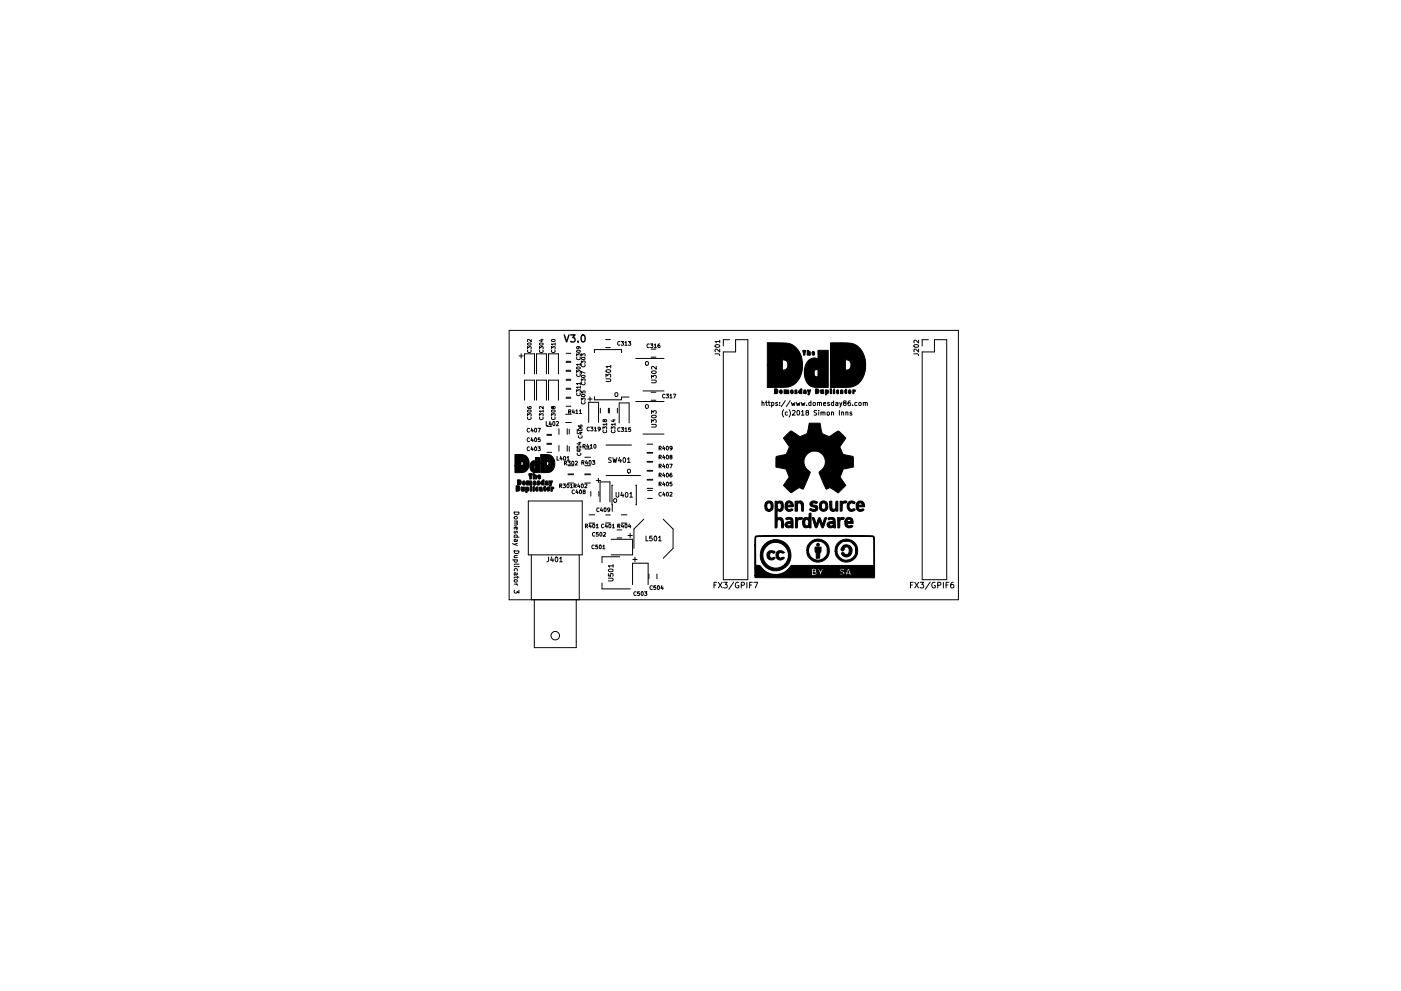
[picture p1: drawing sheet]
<svg xmlns="http://www.w3.org/2000/svg" width="297mm" height="210mm" viewBox="0 0 297 210" stroke-linecap="round" stroke-linejoin="round" font-family="sans-serif">
<path d="M119.6 71.1l.5 1.5 .5-1.5M121 71.1h.9l-.5 .5 .4 .2v.6l-.2 .2-.6-.2M122.6 72.4v.2M123.3 71.2l.3-.1a.8 .8 0 0 1 .5 .7 .8 .8 0 0 1-.5 .8l-.3-.2-.1-.4z" fill="none" stroke="#000" stroke-width=".3"/>
<g fill="none" stroke="#000" stroke-width=".21">
<path d="M107.9 70.1h95.3v57.1h-95.3zM110 75.5h.9M110.5 75.1v.9M111.2 79.3v-4.2h2.1v4.2M111.8 74v-.5l.3 .3 .1-.2h.4v.4M111.9 72.9a.39 .39 0 0 1 .4-.2 .39 .39 0 0 1 .3 .4 .39 .39 0 0 1-.5 .2 .39 .39 0 0 1-.2-.4zM111.9 74.3a.35 .35 0 0 0 .3 .5 .35 .35 0 0 0 .4-.5M112.6 72v.5l-.5-.5-.3 .2 .1 .3M113.8 79.3v-4.2h2.1v4.2M114.4 74v-.5l.3 .3 .1-.2h.3v.4M114.4 72.9a.39 .39 0 0 1 .5-.2 .39 .39 0 0 1 .2 .4 .39 .39 0 0 1-.4 .2 .39 .39 0 0 1-.3-.4zM114.4 74.3a.35 .35 0 0 0 .4 .5 .35 .35 0 0 0 .3-.5"/>
<path d="M114.6 72.1h.6M114.9 72v.5l-.6-.2M116.3 79.3v-4.2h2.1v4.2M116.9 74v-.5l.3 .3 .1-.2h.3v.4M116.9 72.1a.39 .39 0 0 1 .5-.1 .39 .39 0 0 1 .3 .4 .39 .39 0 0 1-.5 .1 .39 .39 0 0 1-.3-.4zM117 74.3a.35 .35 0 0 0 .3 .5 .35 .35 0 0 0 .3-.5M117.7 73h-.8l.2 .2M117.7 72.8v.4M120 78.8h1M120 78.6h1M120 76.9h1M120 76.7h1"/>
<path d="M120 75h1M122.2 79.1v-.5l.3 .3 .1-.2h.4v.4M122.2 75.6v-.5l.3 .2 .1-.2h.4v.5M122.3 78a.39 .39 0 0 1 .4-.2 .39 .39 0 0 1 .3 .4 .39 .39 0 0 1-.4 .2 .39 .39 0 0 1-.3-.4zM122.3 79.4a.35 .35 0 0 0 .3 .5 .35 .35 0 0 0 .4-.5M122.3 75.8a.35 .35 0 0 0 .3 .5 .35 .35 0 0 0 .4-.5M122.3 74.4a.38 .38 0 0 1 .5-.1 .38 .38 0 0 1 .2 .3 .39 .39 0 0 1-.4 .2 .39 .39 0 0 1-.3-.4zM122.6 73.5l.1 .4-.4 .1-.1-.3 .2-.2 .5 .1 .1 .3M123 77.3h-.8l.3 .2M123 77.1v.4M123.3 77.1v-.5l.3 .2v-.2h.4v.5M123.3 75.6v-.5l.3 .2v-.2h.4v.5"/>
<path d="M123.3 75.9a.39 .39 0 0 1 .5-.1 .39 .39 0 0 1 .2 .4 .39 .39 0 0 1-.4 .1 .39 .39 0 0 1-.3-.4zM123.3 79.7a.39 .39 0 0 1 .5-.1 .39 .39 0 0 1 .2 .4 .39 .39 0 0 1-.4 .1 .39 .39 0 0 1-.3-.4zM123.3 77.3a.35 .35 0 0 0 .4 .5 .35 .35 0 0 0 .3-.5M124.1 79.2l-.8-.4v.6M126 74.8v-.6h5.8v.6M128.4 72h1M128.4 73.7h1M128.5 78.6a.49 .49 0 0 1 .6-.2 .49 .49 0 0 1 .3 .5 .49 .49 0 0 1-.5 .2 .49 .49 0 0 1-.4-.5zM129.5 77.8h-1l.3 .3M129.5 77.5v.6M131.4 72.5a.35 .35 0 0 0-.5 .4 .35 .35 0 0 0 .5 .3M131.7 72.5h.5l-.3 .3h.3v.4h-.5"/>
<path d="M132.5 72.7l.2-.2v.8M132.5 73.3h.5M133.2 72.5h.5l-.2 .3h.2v.4h-.5M134.8 76h6M136.9 76.8l.2-.1 .3 .1v.6h-.5zM137.7 73a.35 .35 0 0 0-.5 .4 .35 .35 0 0 0 .5 .3M137.9 73h.5l-.2 .3h.2v.4h-.5M138.1 75.8h1M138.1 74.1h1M138.2 78.8a.49 .49 0 0 1 .5-.2 .49 .49 0 0 1 .4 .5 .49 .49 0 0 1-.6 .2 .49 .49 0 0 1-.3-.5zM138.7 73.2l.3-.2v.8M138.7 73.8h.5"/>
<path d="M139.1 77.7v.7l-.7-.7-.3 .2 .1 .4M139.9 73l-.4 .2v.4l.1 .2 .3-.1v-.4l-.4 .1M151.6 75.1h.9l.1 .3M151.7 73.2a.48 .48 0 0 1 .5-.1 .48 .48 0 0 1 .4 .4 .49 .49 0 0 1-.6 .3 .49 .49 0 0 1-.4-.5zM152.6 74.1v.6l-.7-.6-.3 .2 .1 .3M152.6 72.4h-1l.3 .3M152.6 72.2v.5M153.4 74.7h2.6v-2.6h2.6v50.9h-5.2zM154.7 72.1h-1.3v1.3M193.8 75.1h.8l.2 .3M193.9 73.2a.48 .48 0 0 1 .5-.1 .48 .48 0 0 1 .3 .4 .49 .49 0 0 1-.6 .3 .49 .49 0 0 1-.3-.5zM194.8 74.1v.6l-.8-.6-.2 .2 .1 .3"/>
<path d="M194.8 72.2v.6l-.8-.6-.2 .2 .1 .3M195.5 74.7h2.6v-2.6h2.6v50.9h-5.2zM196.8 72.1h-1.3v1.3M111.2 84.9v-4.2h2.1v4.2M111.8 88.3v-.5l.3 .2 .1-.2h.4v.5M111.8 86.3l.2 .4h.5l.1-.2v-.2h-.4l.1 .4M111.9 88.5a.35 .35 0 0 0 .3 .5 .35 .35 0 0 0 .4-.5M111.9 87.1a.38 .38 0 0 1 .4-.1 .38 .38 0 0 1 .3 .3 .39 .39 0 0 1-.5 .2 .39 .39 0 0 1-.2-.4zM112.3 94.9a.35 .35 0 0 0-.5 .3 .35 .35 0 0 0 .5 .3M112.3 93a.35 .35 0 0 0-.5 .3 .35 .35 0 0 0 .5 .3M112.3 90.9a.35 .35 0 0 0-.5 .4 .35 .35 0 0 0 .5 .3M112.8 94.8l-.2 .5h.5"/>
<path d="M112.8 92.9l-.2 .5h.5M112.8 90.8l-.2 .6h.5M112.9 91.1v.6M112.9 93.2v.5M112.9 95.1v.5M113.4 94.9l.1-.1a.37 .37 0 0 1 .3 .4 .37 .37 0 0 1-.4 .3zM113.4 93l.1-.1a.37 .37 0 0 1 .3 .4 .37 .37 0 0 1-.4 .3zM113.4 90.9h.1a.37 .37 0 0 1 .3 .4 .37 .37 0 0 1-.4 .3zM113.8 84.9v-4.2h2.1v4.2M114.1 94.8h.4l-.2 .3 .2 .1v.3h-.4M114.1 90.9h.5l-.4 .8M114.4 88.3v-.5l.3 .2 .1-.2h.3v.5"/>
<path d="M114.4 88.5a.35 .35 0 0 0 .4 .5 .35 .35 0 0 0 .3-.5M114.5 92.9h-.4v.4l.4-.1v.4h-.4M115.2 87.2h-.8l.2 .3M115.2 86.2v.5l-.6-.5-.2 .2v.3M115.2 87v.5M115.8 89.4v.9h.4M116 96h1M116 94.3h1M116 94.1h1M116 92.4h1M116 92.2h1M116 90.5h1"/>
<path d="M116.3 84.9v-4.2h2.1v4.2M116.6 89.4l-.2 .6h.5M116.8 89.7v.6M116.9 88.3v-.5l.3 .2 .1-.2h.3v.5M116.9 87.1a.39 .39 0 0 1 .5-.2 .39 .39 0 0 1 .3 .4 .39 .39 0 0 1-.5 .2 .39 .39 0 0 1-.3-.4zM117 88.5a.35 .35 0 0 0 .3 .5 .35 .35 0 0 0 .3-.5M117.3 86.4l.3-.1v.4a.33 .33 0 0 1-.3-.1 .33 .33 0 0 1-.1-.3h-.3v.2l.2 .2 .2-.2M117.3 89.5l.1-.1a.45 .45 0 0 1 .3 .5 .45 .45 0 0 1-.4 .4l-.1-.3zM118 89.5l.3-.1 .1 .3-.5 .6h.5M118.1 96.8v.8h.4M118.5 91v1.2M118.5 94.5v1.2"/>
<path d="M118.9 96.8l-.2 .6h.5M119.1 97.1v.5M119.6 96.9l.1-.1a.37 .37 0 0 1 .3 .5 .37 .37 0 0 1-.4 .3zM119.7 98.3l.4-.1v-.3h-.4v.8M119.9 98.3l.2 .4M119.9 89.6h1.2M119.9 87.9h1.2M120 80.5h1M120 86.2h1M120 84.5h1M120 80.7h1M120 82.4h1"/>
<path d="M120 84.3h1M120 82.6h1M120.2 97.1l.3-.3v.8M120.2 97.6h.5M120.3 91v1.2M120.3 94.5v1.2M120.4 97.9h.5l-.3 .3h.3v.4h-.5M120.4 98.8h1.2M120.6 87.4l.3-.1 .1-.3-.4-.1v.8M120.7 91.1v1M120.7 94.7v1M120.8 87.4l.2 .3"/>
<path d="M121.3 97.9h.1a.37 .37 0 0 1 .3 .4 .37 .37 0 0 1-.4 .3zM121.5 86.9l-.2 .6h.5M121.7 87.2v.5M122 97.9h.3l.1 .2-.5 .6h.5M122.1 87.2l.2-.3v.8M122.1 87.7h.4M122.2 83.2v-.5l.3 .2 .1-.2h.4v.5M122.3 83.4a.35 .35 0 0 0 .3 .5 .35 .35 0 0 0 .4-.5M122.4 91.1v1M122.4 94.7v1M122.4 94.7a.39 .39 0 0 1 .5-.1 .39 .39 0 0 1 .2 .4 .39 .39 0 0 1-.4 .1 .39 .39 0 0 1-.3-.4zM122.4 96.1a.35 .35 0 0 0 .4 .5 .35 .35 0 0 0 .3-.5"/>
<path d="M122.6 90.2l.2 .4h.5l.1-.1-.1-.3h-.3l.1 .4M122.6 95.5h.6M122.6 93.9h.6M122.7 91a.39 .39 0 0 1 .4-.1 .39 .39 0 0 1 .3 .4 .39 .39 0 0 1-.5 .1 .39 .39 0 0 1-.2-.4zM122.7 92.5a.35 .35 0 0 0 .3 .5 .35 .35 0 0 0 .3-.5M122.9 87.2l.2-.3v.8M122.9 87.7h.4M122.9 91.8h.5M122.9 95.3v.5l-.6-.2M122.9 93.8v.5l-.6-.2M123 82.1h-.8l.3 .3M123 81.4h-.8l.3 .2"/>
<path d="M123 81.2v.4M123 81.9v.5M123.2 91.7v.5l-.6-.2M123.3 85v-.5l.3 .2v-.2h.4v.5M123.3 83v.4h.3v-.4h.4v.4M123.3 80.9v-.5l.3 .3v-.3h.4v.5M123.3 83.8a.39 .39 0 0 1 .5-.2 .39 .39 0 0 1 .2 .4 .39 .39 0 0 1-.4 .2 .39 .39 0 0 1-.3-.4zM123.3 85.2a.35 .35 0 0 0 .4 .5 .35 .35 0 0 0 .3-.5M123.3 81.2a.35 .35 0 0 0 .4 .5 .35 .35 0 0 0 .3-.5M123.4 98.1h.3l.1-.3-.4-.1v.8M123.6 98.1l.2 .4M123.6 94.7h.4v-.3l-.4-.1v.8"/>
<path d="M123.8 94.7l.3 .4M124 98.8h1.2M124 95.3h1.2M124 97h1.2M124.3 97.7l-.2 .6h.5M124.5 98v.5M124.6 94.3l-.2 .5h.5M124.6 84.7h1M124.8 94.6v.5M124.8 89.6v-4.2h2.1v4.2M125 90.7a.35 .35 0 0 0-.5 .3 .35 .35 0 0 0 .5 .3M125 97.8l.1-.1a.37 .37 0 0 1 .3 .4 .37 .37 0 0 1-.4 .4z"/>
<path d="M125.1 84.2v.9M125.1 94.5l.3-.2v.8M125.1 95.1h.5M125.2 90.6h.5l-.2 .3 .2 .1v.3h-.5M125.6 97.7h.5l-.3 .3 .3 .1v.4h-.5M126 94.3h.1a.37 .37 0 0 1 .3 .4 .37 .37 0 0 1-.4 .3zM126 90.8l.3-.2v.8M126 91.4h.5M126 84.2v.6h5.8v-.6h1.6M127.2 91l-.3 .1-.1-.4 .3-.1 .1 .2v.4l-.3 .2M127.3 86.6v1M127.8 91v-.4l.3 .2 .1-.2h.4v.4"/>
<path d="M127.9 91.3a.35 .35 0 0 0 .3 .5 .35 .35 0 0 0 .4-.5M128.2 89.2l.4-.1v.3a.33 .33 0 0 1-.4 0 .33 .33 0 0 1-.1-.3h-.2l-.1 .2 .2 .2 .2-.2M128.5 80.4h.8l.2 .2-.2 .4h-.8M128.5 80v-.6l.4 .3 .1-.3h.4v.6M128.5 94.4h5.4M128.6 90h-.8l.3 .2M128.6 89.8v.4M129 86.6v1M129.2 86.6v1M129.6 97.2h-.5a.42 .42 0 0 0 .5 .5l-.1 .4h-.5M129.6 91v-.4l.3 .2 .1-.2h.3v.4M129.7 91.3a.35 .35 0 0 0 .3 .5 .35 .35 0 0 0 .3-.5"/>
<path d="M129.9 89.1h.5M129.9 97.1l.3 1 .2-.7 .2 .7 .2-1M130.1 89v.5l-.5-.2M130.4 90h-.8l.2 .2M130.4 89.8v.4M130.4 83.4l.2-.1 .3 .1v.6h-.5zM130.9 86.6v1M131.3 89.7v-4.2h2.1v4.2M131.4 97.1l-.3 .7h.6M131.4 90.8a.35 .35 0 0 0-.5 .3 .35 .35 0 0 0 .5 .4M131.6 97.4v.7M131.7 90.7h.5l-.3 .3 .3 .1v.4h-.5"/>
<path d="M132.2 97.2l.1-.1a.49 .49 0 0 1 .4 .5 .49 .49 0 0 1-.5 .5l-.1-.4zM132.5 91l.2-.3v.8M132.5 91.5h.5M133 97.4l.3-.3v1M133 98.1h.6M133.1 99.7l.2-.1 .3 .1-.1 .6-.4-.1zM133.7 90.7h-.4v.4h.3l.1 .4h-.4M134.8 85.2h6M136.3 82.9h4.5M136.3 92.1h4.5M136.9 86l.2-.2 .3 .2v.6l-.5-.1zM137.2 100h1.2"/>
<path d="M137.2 96h1.2M137.2 94.2h1.2M137.2 98h1.2M137.2 99.8h1.2M137.2 96.1h1.2M137.2 97.9h1.2M138.1 84.9h1M138.1 83.2h1M138.1 80.6h.8l.2 .2-.2 .4h-.8M138.1 80.3v-.7l.4 .4 .1-.3h.4v.6M138.1 90h.8l.2 .2-.2 .4h-.8M138.1 89.7v-.7l.4 .4 .1-.3h.4v.6"/>
<path d="M138.1 87.8v-.7l.4 .4 .1-.3h.4v.6M138.2 88.2a.49 .49 0 0 1 .5-.2 .49 .49 0 0 1 .4 .5 .49 .49 0 0 1-.6 .2 .49 .49 0 0 1-.3-.5zM139.7 98.9h.4l.1-.3-.5-.1v.8M139.7 97h.4l.1-.3-.5-.1v.8M139.7 95.1h.4l.1-.3-.5-.1v.8M139.9 98.9l.3 .4M139.9 97l.3 .4M139.9 95.1l.3 .4M140.7 98.5l-.2 .5h.5M140.7 96.5l-.2 .6h.5M140.7 94.6l-.2 .6h.5M140.9 94.9v.6"/>
<path d="M140.9 96.9v.5M140.9 98.8v.5M141 83.7a.35 .35 0 0 0-.5 .3 .35 .35 0 0 0 .5 .4M141.2 83.6h.5l-.2 .3 .2 .1v.4h-.5M141.3 98.6l.2-.1a.37 .37 0 0 1 .2 .4 .37 .37 0 0 1-.4 .3zM141.3 96.7l.2-.1a.37 .37 0 0 1 .2 .4 .37 .37 0 0 1-.4 .3zM141.3 94.8l.2-.1a.37 .37 0 0 1 .2 .4 .37 .37 0 0 1-.4 .3zM142 98.5h.5l-.3 .8M142 83.9l.3-.3v.8M142 84.4h.5M142.2 96.9l-.2-.1 .2-.2 .2 .1v.2a.32 .32 0 0 0-.3 .1 .32 .32 0 0 0 0 .3h.3l-.1-.4M142.5 95l-.4 .1v-.3l.2-.1 .2 .1-.1 .5-.3 .2"/>
<path d="M142.8 83.6h.5l-.4 .8M161.6 85.5l.3-.1 .1 .6M161.6 85v1M162.3 85.4h.4M162.5 85v.9l.2 .1M162.9 85.4h.4M163 85v.9l.3 .1M163.6 85.4h.3l.2 .2-.1 .4h-.4M163.6 85.4v1M164.8 85.4l-.3 .1 .3 .3v.2h-.3M165.3 85.9v.1M165.3 85.4v.1"/>
<path d="M166.2 86.9a1.15 1.15 0 0 0 0 1.6M166.5 85l-.9 1.3M167 87.5l-.3-.1-.2 .2 .1 .4h.4M167.3 86.9a1.15 1.15 0 0 1 0 1.6M167.6 85l-.9 1.3M167.8 85.4l.2 .6 .2-.4 .2 .4 .2-.6M168 87.2l.4-.1 .2 .3-.6 .7h.6M168.8 85.4l.2 .6 .2-.4 .2 .4 .2-.6M169.1 87.1h.1a.49 .49 0 0 1 .4 .5 .49 .49 0 0 1-.5 .4l-.1-.3zM169.9 85.4l.2 .6 .2-.4 .2 .4 .1-.6M169.9 87.4l.3-.3v1M169.9 88.1h.6"/>
<path d="M171 85.9v.1M171.1 87.5l-.2-.3 .4-.1 .1 .3-.5 .3 .2 .4 .3-.2-.1-.4M171.9 85.4h-.3l-.1 .2 .1 .4h.3M171.9 85v1M172.4 85.5h.4v.5l-.4-.1zM173.2 87.1l-.6 .1a.42 .42 0 0 0 .5 .5v.3h-.5M173.3 85.5l.4-.1v.6M173.3 85.4v.6M173.6 87.1v.1M173.6 87.4v.7M173.7 85.5l.4-.1 .1 .6M174.1 87.5h.3l.1 .6"/>
<path d="M174.1 87.4v.7M174.5 87.6l.4-.1v.6M174.6 85.7l.5-.1-.1-.2h-.3l-.1 .1v.5h.4M175.4 87.5h.4v.5h-.4zM175.8 85.4l-.3 .1 .3 .3v.2h-.3M176.3 87.5h.4v.6M176.3 87.4v.7M176.7 85.4h-.2l-.2 .2 .1 .4h.3M176.7 85v1M177.2 85.4h.4v.6M177.6 85.6l-.4 .2 .1 .2h.3M178 87.1v1"/>
<path d="M178 85.4l.3 .6M178.4 87.5h.4l.1 .6M178.4 87.4v.7M178.5 85.4l-.5 1M179 85.5l-.1-.4h.4l.1 .3-.6 .3 .2 .3 .4-.1-.2-.4M179.3 87.5h.4l.1 .6M179.3 87.4v.7M180.3 85l-.5 .3v.6l.2 .1 .3-.1v-.4l-.3-.1-.2 .2M180.6 87.5l-.4 .1 .4 .2v.2h-.4M180.8 85.9v.1M181.7 85.4h-.3l-.2 .2 .1 .4h.4M182.2 85.4h.2l.2 .2v.3l-.2 .1-.3-.1z"/>
<path d="M183 85.5l.4-.1 .1 .6M183 85.4v.6M183.5 85.5l.3-.1 .1 .6M108.7 115.3l1 .4M108.7 118.8h.9v.4h-.5v-.4M109 108.6h1a.51 .51 0 0 1-.5 .6 .51 .51 0 0 1-.5-.6zM109 116.9h1a.51 .51 0 0 1-.5 .6 .51 .51 0 0 1-.5-.6zM109 110.5h.7M109 114h1M109 118.3h.7M109.1 109.7l.4-.1 .2 .3-.2 .2h-.3l-.2-.2zM109.1 112.7v.4h.2l.2-.4 .2 .1-.1 .3"/>
<path d="M109.1 114l-.1-.3 .2-.2 .4 .1v.4M109.1 114.9l-.1-.4 .2-.1 .2 .1 .1 .4M109.4 111.8l.1 .5h.1l.1-.3-.2-.2-.4 .1v.4M109.5 111l.1 .4h-.6M109.6 110.5v.4l-.6 .1M109.6 114.5v.3l-.6 .1M109.7 117.9h-.6v.4M109.7 115.3l-.7 .2M110 119.7h-.8l-.2 .1M112 106.3h11.4v11.4h-11.4zM112.6 117.7v9.5M116.3 118.2v.8l-.4 .2"/>
<path d="M117 118.1l-.3 .8h.7M117.2 118.5v.7M117.8 118.2h.1a.49 .49 0 0 1 .4 .5 .49 .49 0 0 1-.5 .4l-.1-.3zM118.6 118.5l.3-.3v1M118.6 119.2h.6M118.7 103.1h.3l.1-.3-.4-.1v.8M118.9 103.1l.2 .4M119.4 102.7h.5l-.3 .3 .2 .1v.3h-.4M120.3 102.8l.1-.1a.37 .37 0 0 1 .3 .4 .37 .37 0 0 1-.4 .3zM120.4 100.7h1.2M120.4 102.5h1.2M120.4 100.6h1.2"/>
<path d="M120.9 102.9l.3-.2v.8M120.9 103.5h.5M121.7 103.1h.4v-.3l-.4-.1v.8M121.8 104a.35 .35 0 0 0-.5 .4 .35 .35 0 0 0 .5 .3M121.9 103.1l.3 .4M122.3 103.9l-.2 .6h.5M122.5 104.2v.6M122.7 102.6l-.2 .6h.5M122.8 117.7v9.5M122.9 102.9v.6M122.9 104h.1a.37 .37 0 0 1 .3 .4 .37 .37 0 0 1-.4 .3zM123.3 102.8l.1-.1a.37 .37 0 0 1 .3 .4 .37 .37 0 0 1-.4 .3z"/>
<path d="M123.8 104.3l-.2-.2 .2-.1h.2v.2a.32 .32 0 0 0-.3 .1 .32 .32 0 0 0 0 .4h.3l-.1-.4M124 100.7h1.2M124 102.5h1.2M124 100.6h1.2M124 102.8l.3-.1 .2 .2-.5 .6h.5M124.1 111.6h.4v-.3l-.4-.1v.8M124.3 111.6l.3 .4M124.9 109.2h1.2M124.9 111h1.2M125.1 111.2l-.2 .5h.5M125.3 104.3v1M125.3 111.5v.5"/>
<path d="M125.7 111.3l.1-.1a.37 .37 0 0 1 .3 .4 .37 .37 0 0 1-.4 .3zM126 115.7a.35 .35 0 0 0-.5 .3 .35 .35 0 0 0 .5 .4M126.1 113a.35 .35 0 0 0-.5 .4 .35 .35 0 0 0 .5 .3M126.4 111.4l.2-.2v.8M126.4 112h.5M126.4 101.9h.9M126.7 115.6h-.4v.4h.4v.4h-.4M126.8 113h-.4v.3h.4v.4h-.4M126.9 101.5v.9M127 104.3v1M127 107.8a.35 .35 0 0 0-.5 .4 .35 .35 0 0 0 .5 .3M127.1 115.7l.1-.1a.37 .37 0 0 1 .3 .5 .37 .37 0 0 1-.4 .3z"/>
<path d="M127.2 106.5v-4.3h2.1v4.3M127.2 113h.2a.37 .37 0 0 1 .3 .4 .37 .37 0 0 1-.5 .3zM127.5 107.7l-.2 .6h.5M127.7 108v.6M127.8 115.9l.2-.3v.8M127.8 116.4h.5M127.9 113h.3l.2 .2-.5 .6h.5M128 111.3a.35 .35 0 0 0-.5 .3 .35 .35 0 0 0 .5 .3M128.1 107.8h.2a.37 .37 0 0 1 .2 .4 .37 .37 0 0 1-.4 .3zM128.4 111h1M128.4 109.3h1M128.5 100.9h7.3"/>
<path d="M128.5 111.2l-.2 .5h.5M128.7 111.5v.5M129.2 111.2h.1a.37 .37 0 0 1 .3 .4 .37 .37 0 0 1-.4 .3zM129.3 108.1l-.4 .1v-.4h.2l.2 .1-.1 .5-.3 .2M129.6 114.4h4.5v3.3h-4.5M129.8 111.4l.3-.2v.8M129.8 112h.5M129.9 102.9h-.1v5.6M130 119.8v.5M130.2 105.9l.1-.1 .4 .1-.1 .6h-.4zM130.6 104.5v.8l.2 .2 .4-.2v-.8M130.8 114.1h1"/>
<path d="M130.8 112.4h1M131 111.6h.4v-.3l-.4-.1v.8M131.2 111.6l.2 .4M131.4 118.1h-3.8v1.3M131.7 109.2h1.2M131.7 111h1.2M131.9 104.4l-.3 .7h.6M131.9 111.2l-.2 .5h.5M132.1 104.8v.7M132.1 111.5v.5M132.6 111.2h.1a.37 .37 0 0 1 .3 .4 .37 .37 0 0 1-.4 .3zM132.7 104.6l.1-.1a.49 .49 0 0 1 .4 .5 .49 .49 0 0 1-.5 .4l-.1-.3z"/>
<path d="M133.1 113.6h1M133.5 111.2l-.2 .5h.5M133.5 104.8l.3-.3v1M133.5 105.5h.6M133.6 113.2v.9M133.6 111.5v.5M134.2 118.7h.9M134.6 118.2v1M134.8 102.9h.1v4.2h-.1M136.5 110.1l-2.1 2.1v4.1M137 113.7v1h.4M137.2 103.6h1.2"/>
<path d="M137.2 101.9h1.2M137.2 101.7h1.2M137.3 104h1M137.3 105.7h1M138.2 113.7h-.4l-.1 .5h.5v.5h-.5M138.8 113.8l.1-.1a.49 .49 0 0 1 .4 .6 .49 .49 0 0 1-.5 .4l-.1-.3zM139.6 114l.3-.3v1M139.6 114.7h.6M139.7 102.7h.4l.1-.3-.5-.1v.8M139.7 100.8h.4l.1-.3-.5-.1v.8M139.9 102.7l.3 .4M139.9 100.8l.3 .4"/>
<path d="M140.2 104.5a.35 .35 0 0 0-.5 .4 .35 .35 0 0 0 .5 .3M140.6 110.1l2.1 2.1v4.1l-2.1 2.1M140.7 104.4l-.2 .6h.5M140.7 102.3l-.2 .5h.5M140.7 100.4l-.2 .5h.5M140.9 100.7v.5M140.9 102.6v.5M140.9 104.7v.6M141.3 104.5h.2a.37 .37 0 0 1 .2 .4 .37 .37 0 0 1-.4 .3zM141.3 102.4l.2-.1a.37 .37 0 0 1 .2 .4 .37 .37 0 0 1-.4 .3zM141.3 100.5l.2-.1a.37 .37 0 0 1 .2 .4 .37 .37 0 0 1-.4 .3zM142 104.5h.3l.2 .2-.5 .6h.5"/>
<path d="M142.4 100.4l-.3 .2-.1 .4 .2 .2 .2-.1v-.4l-.4 .2M142.4 102.3h-.3l-.1 .4 .4-.1v.4h-.4M109 120.2h.7M109 123.9h.7M109.1 121.1l-.1-.3 .2-.2 .4 .1v.4M109.1 122l-.1-.4 .2-.1h.2l.1 .5M109.1 123h.5v.4l-.5 .1zM109.1 125.2l-.1 .4 .2 .2h.3l.1-.3 .4 .3v-.6M109.5 123.9l.2 .3M109.6 121.5v.4l-.6 .1M109.7 122.3v.4M109.9 120.2h.1"/>
<path d="M110 122.5h-.8l-.2 .2M113.3 127.2v10.2h8.9v-10.2M127.6 123.7v1.2h6M129 122.7h.8l.2 .2-.2 .3h-.8M129 121.7v.5h.5l-.1-.4 .5-.1v.5M129 120.9a.49 .49 0 0 1 .6-.2 .49 .49 0 0 1 .3 .5 .49 .49 0 0 1-.5 .2 .49 .49 0 0 1-.4-.5zM130 120.1h-1l.3 .2M134.1 124v-4.5h3.3v4.5M134.9 125.6a.35 .35 0 0 0-.5 .3 .35 .35 0 0 0 .5 .4M135.6 125.5h-.4v.4h.4v.4h-.4M136 125.6l.1-.1a.37 .37 0 0 1 .3 .5 .37 .37 0 0 1-.4 .3zM136.7 125.5h.5l-.3 .3 .2 .1v.4h-.4"/>
<path d="M137.6 121.8v1M138.3 124.3a.35 .35 0 0 0-.5 .4 .35 .35 0 0 0 .5 .3M139 124.3h-.4v.4l.4-.1v.4h-.4M139.3 121.8v1M139.5 124.3h.1a.37 .37 0 0 1 .2 .4 .37 .37 0 0 1-.4 .3zM140.3 124.2l-.2 .6h.5M140.5 124.5v.6M151.4 124.1h.4M152 123.5h-.6v1.2M152.3 123.5l.8 1.2M153.1 123.5l-.8 1.2M153.4 123.5h.8l-.4 .5 .3 .1v.5l-.1 .1-.6-.1"/>
<path d="M155.6 123.5l-1.1 1.5M156.6 123.6a.55 .55 0 0 0-.7 .6 .55 .55 0 0 0 .7 .4v-.4h-.2M157.2 124.2l.5-.1 .1-.4-.6-.2v1.2M158.4 123.5v1.2M158.9 124.1h.4M159.5 123.5h-.6v1.2M159.8 123.5h.8l-.5 1.2M193 124.1h.4M193.6 123.5h-.6v1.2M194 123.5l.8 1.2M194.8 123.5l-.8 1.2M195.1 123.5h.7l-.4 .5 .4 .1v.5l-.2 .1-.5-.1"/>
<path d="M197.2 123.5l-1 1.5M198.2 123.6a.55 .55 0 0 0-.7 .6 .55 .55 0 0 0 .8 .4v-.4h-.2M198.8 124.2l.6-.1v-.4l-.6-.2v1.2M200 123.5v1.2M200.6 124.1h.4M201.2 123.5h-.6v1.2M202.1 123.5l-.3 .1-.2 .2v.7l.2 .2 .4-.1-.1-.5-.3-.1-.2 .2"/>
<circle cx="117.7" cy="134.9" r=".9"/>
</g>
<g fill="#000" stroke="#000" stroke-width=".21">
<path d="M162.7 72.7h2.5a4 4 0 0 1 4.7 3 5.2 5.2 0 0 1-2.2 6.2l-1.1 .3h-3.9v-4.7h3.2v1a1.06 1.06 0 0 0 1.2-1 1.06 1.06 0 0 0-1.2-1.1v1.1h-3.2zM170.2 74.3h.6l-.1 1h-.4zM171.2 74.3l.2 .1 .1 .2h.2l.1 .7h-.3v-.5v.5h-.3zM172.3 74.6a.25 .25 0 0 1 .3 .1 .25 .25 0 0 1 0 .3h-.2l.3 .1v.2h-.4l-.1-.5h.4h-.4zM173.4 74.3h2.2v7.9h-1.7a2.72 2.72 0 0 1-3.4-3h2.1l.1 .5 .6 .2h.1v-.6a.55 .55 0 0 0-.3-.9l-.3 .1-.2 .7h-2.1a2.83 2.83 0 0 1 2-3.2l.9 .1zM176.1 72.7h2.7a4.1 4.1 0 0 1 4.7 4.3 4.3 4.3 0 0 1-3.3 5.1l-4.1 .1v-3.7h3.1a1.11 1.11 0 0 0 1.2-1.1 1.11 1.11 0 0 0-1.2-1.1v2.2h-3.1zM109.2 96.4a2.99 2.99 0 0 1 2.5 .5 2.01 2.01 0 0 1-.9 3.3l-1.6 .1v-1.5h1.2a.42 .42 0 0 0 .6-.4 .42 .42 0 0 0-.5-.4l-.1 .8h-1.2zM113.5 97.1h.9v3.2h-1.1a1.07 1.07 0 0 1-.9-1.3h.8l.1 .3h.2l-.1-.6-.2 .3h-.8a.95 .95 0 0 1 1.1-1.2zM114.6 96.4h.9a1.93 1.93 0 0 1 2.1 1.6 1.93 1.93 0 0 1-1.5 2.2l-1.5 .1v-2.1h1.3v.5a.38 .38 0 0 0 .5-.4 .38 .38 0 0 0-.5-.3v.2h-1.3zM164.2 82.5a.54 .54 0 0 1 .7 .5 .54 .54 0 0 1-.7 .5v-.5l.4 .1v-.1v-.1l-.4 .1zM165.4 82.8a.36 .36 0 0 1 .5 .3 .36 .36 0 0 1-.5 .4l-.1-.4h.3h-.3zM166.2 82.7h.9l.2 .8h-.3l-.1-.5v.5h-.3v-.5l-.1 .5h-.3z"/>
<path d="M167.7 82.8l.4 .1 .1 .3h-.3l.3 .2a.33 .33 0 0 1-.5 .1 .33 .33 0 0 1-.1-.5h.4h-.4zM168.6 82.7l.4 .1-.2 .2a.27 .27 0 0 1 .2 .3 .27 .27 0 0 1-.2 .2h-.3l.1-.2h.2l-.3-.3zM169.5 82.8l.5-.3v1l-.6-.1v-.2h.4l-.1-.2-.1 .2h-.2zM170.4 82.8a.34 .34 0 0 1 .5 0 .34 .34 0 0 1 0 .4v.3h-.5v-.2h.2h-.2l.2-.2-.2-.1zM171.2 82.7h.2l.1 .2 .1-.1 .3-.1-.1 .2a.78 .78 0 0 1-.4 .9l-.1-.1 .1-.3zM172.9 82.5a.54 .54 0 0 1 .7 .5 .54 .54 0 0 1-.7 .5v-.5l.4 .1v-.1v-.1l-.4 .1zM166.8 92.2l.9-.8 1.9 1.2 1.3-.5 .3-.2 .4-2.1h2.3l.2 1.4a1.02 1.02 0 0 0 1.1 1.2l.7 .3 1.8-1.3 .9 .8 .7 .8-1.2 1.8 .3 .8a1.02 1.02 0 0 0 1.3 1l1.2 .3v2.2l-2.1 .4-.7 1.7 1.2 1.8-1.6 1.6-1.1-.8a.97 .97 0 0 0-1.4 0l-1.5-3.6a2.41 2.41 0 0 0 1.3-2.3 2.41 2.41 0 0 0-1.7-2.1 2.35 2.35 0 0 0-2.7 1.5 2.35 2.35 0 0 0 1.2 2.9l-1.5 3.6a1.04 1.04 0 0 0-1.4 0l-1.2 .8-1.6-1.6 1.2-1.8-.7-1.7-2.1-.4 .1-2.2 1.2-.3a1.02 1.02 0 0 0 1.2-1l.4-.8-1.3-1.8zM174 82.7h.2l.1 .6 .1-.6h.2v.8h-.5zM175 82.7a.45 .45 0 0 1 .6 .2 .45 .45 0 0 1-.2 .6l-.4 .3v-.7h.3v.2l.1-.2h-.4zM176 82.5h.3v1h-.3zM176.7 82.8h.3v.7h-.3zM177.4 82.8h.4v.3h-.2l.2 .1a.27 .27 0 0 1-.3 .3 .27 .27 0 0 1-.2-.4z"/>
<path d="M178.2 82.8a.33 .33 0 0 1 .4 0 .33 .33 0 0 1 .1 .4v.3h-.5v-.2h.3h-.3l.2-.3h-.2zM179.3 82.6l.2 .2v.7a.5 .5 0 0 1-.4-.4 .5 .5 0 0 1 .2-.5zM180 82.8a.35 .35 0 0 1 .4 .3 .35 .35 0 0 1-.4 .4l-.1-.4h.3h-.3zM180.8 82.7h.5v.3a.33 .33 0 0 0-.3 .5h-.2zM109.4 103.1a.59 .59 0 0 1 .8 .4 .59 .59 0 0 1-.4 .7h-.4v-.6h.4v.2l.1-.2-.1-.1v.1h-.4zM109.7 101.8a.59 .59 0 0 1 .8 .6 .59 .59 0 0 1-.8 .5v-.5l.4 .1 .1-.2-.1-.1-.4 .2zM110.5 103.3l.2 .1 .1 .5 .1-.6h.3v.9h-.6zM110.9 102.1a.4 .4 0 0 1 .5 .4 .4 .4 0 0 1-.5 .4l-.1-.4 .3 .1 .1-.2-.4 .1zM111.5 103.3h.2a.45 .45 0 0 1 .5 .5 .45 .45 0 0 1-.4 .4l-.1 .3h-.2v-.7l.3 .1 .1-.1-.1-.1-.3 .1zM111.6 102l.7 .1 .3-.1 .2 .9h-.3l-.1-.6-.1 .6h-.2l-.1-.6-.1 .6h-.3zM112.4 103.1h.3v1.1h-.3zM112.1 100.5h.7l-.2 1.1h-.3z"/>
<path d="M113.2 103.1v.2zM113 100.5h.3l.1 .3h.3v.8h-.2l-.1-.6-.1 .6h-.3zM113 103.4h.3v.8h-.3zM113.1 102.1h.4l.2 .4-.4 .1h.3a.36 .36 0 0 1-.5 .3 .36 .36 0 0 1 0-.6l.4 .1-.1-.2-.3 .1zM113.6 103.4l.4-.1a.25 .25 0 0 1 .1 .3 .25 .25 0 0 1-.3 .2l.3 .2a.3 .3 0 0 1-.4 .2 .3 .3 0 0 1-.2-.4zM114 102.1h.4v.2h-.3a.32 .32 0 0 1 .4 .2 .32 .32 0 0 1-.2 .4 .32 .32 0 0 1-.4-.2h.2l-.2-.4zM114.1 100.8a.28 .28 0 0 1 .4 0 .28 .28 0 0 1 0 .4l-.2 .1 .3 .1a.33 .33 0 0 1-.4 .2 .33 .33 0 0 1-.2-.5v-.1h.5h-.5zM114.4 103.4a.36 .36 0 0 1 .4 0 .36 .36 0 0 1 .2 .4v.4h-.5l-.2-.2 .4-.1-.4 .1 .3-.3-.2-.1zM114.8 102.1l.6-.3v1.1l-.6-.1-.1-.3 .3 .1 .1-.1-.1-.1-.1 .1h-.2zM115.6 103.1l.1 1a.32 .32 0 0 1-.4 0 .32 .32 0 0 1 0-.4l-.1-.2zM115.7 102.1a.36 .36 0 0 1 .4 0 .36 .36 0 0 1 .1 .4l.1 .4-.6-.1-.1-.2 .4 .1-.4-.1 .3-.2-.2-.1zM116 103.4l.1-.1a.41 .41 0 0 1 .4 .5 .41 .41 0 0 1-.5 .3l-.1-.4 .4 .1-.1-.2-.3 .1z"/>
<path d="M116.8 103.3l.6 .1a.21 .21 0 0 1 0 .3 .21 .21 0 0 1-.3 0v.5h-.3zM116.4 102l.4 .2v-.2h.3l-.3 1.1-.3 .1 .1-.5zM162.4 106.6a.91 .91 0 0 1 1.1-.2 .91 .91 0 0 1 .4 1.1 .89 .89 0 0 1-.9 1 .89 .89 0 0 1-.8-1.2h.4a.57 .57 0 0 0 .6 .8 .74 .74 0 0 0 .3-.8 .74 .74 0 0 0-.6-.6l-.3 .6h-.4zM162.8 117.2a1.06 1.06 0 0 1 1.5 0l-.3 .2-.4-.2a.6 .6 0 0 0-.5 .8 .6 .6 0 0 0 1 .2l.2 .1a.97 .97 0 0 1-1.4 .3 .97 .97 0 0 1-.1-1.4zM162.2 115.5a3.3 3.3 0 0 1 5.1 .6 3.3 3.3 0 0 1-1.9 4.8 3.3 3.3 0 0 1-4.2-3.1h.5a2.72 2.72 0 0 0 4 2.5 2.72 2.72 0 0 0 .4-4.6 2.72 2.72 0 0 0-4.3 1.5l-.1 .6h-.5a3.1 3.1 0 0 1 1-2.3zM164.7 117.1a1.14 1.14 0 0 1 1.6 .1l-.3 .2a.56 .56 0 0 0-.8 0 .56 .56 0 0 0 0 .8 .56 .56 0 0 0 .7 0l.4 .1a.99 .99 0 0 1-1.5 .3 .99 .99 0 0 1-.1-1.5zM164.3 106.3l.5 .1a.88 .88 0 0 1 1 0 .88 .88 0 0 1 .3 1 .81 .81 0 0 1-.3 1 .81 .81 0 0 1-1-.1v1.7a.84 .84 0 0 1 1-.1 .84 .84 0 0 1 .3 .9v1.2h-.4v-.4a1.07 1.07 0 0 0-.6-1.4 1.32 1.32 0 0 0-.3 1.4l-.1 .4h-.4v-4.6h.5l.1 .6a.39 .39 0 0 0 .7-.2v-.8l-.4-.3a.59 .59 0 0 0-.4 .7h-.5zM166.6 110a.98 .98 0 0 1 1.2-.1 .98 .98 0 0 1 .3 1.2v.9l-.4-.1a.87 .87 0 0 1-1.3-.6l.9 .3 .4-.1v-.2v-.2h-.6l-.3 .2h-.4l.1-.2a1.38 1.38 0 0 1 1.2-.5 .48 .48 0 0 0-.3-.5 .48 .48 0 0 0-.5 .2zM166.7 106.5a.92 .92 0 0 1 1.1 0 .92 .92 0 0 1 .4 1l-1.3 .1a.54 .54 0 0 0 .4 .5 .54 .54 0 0 0 .6-.1l.2 .2a1 1 0 0 1-1.3 .1 1 1 0 0 1-.3-1.3l1.3 .1a.45 .45 0 0 0-.4-.4 .45 .45 0 0 0-.5 .3h-.4zM168.7 109.8l1.5 .1a.51 .51 0 0 1-.7 .3 1.3 1.3 0 0 0-.4 1.5l-.1 .3h-.3zM168.6 106.3a1.58 1.58 0 0 1 1.7 .4v1.8l-.3-.1-.1-1a.44 .44 0 0 0-.2-.7 .44 .44 0 0 0-.6 .4v1.4h-.5zM170.3 110a1 1 0 0 1 1.2 0 .94 .94 0 0 1 .2-1.1h.3v3.1h-.4l-.1-.2a.86 .86 0 0 1-1.1 0 .86 .86 0 0 1-.2-1h.4a.56 .56 0 0 0 .6 .7 .77 .77 0 0 0 .3-.7 .77 .77 0 0 0-.5-.6l-.4 .6h-.4z"/>
<path d="M172.2 109.9l.1-.1a.97 .97 0 0 1 .6 1.2l.2 .2 .4-1.2 .3-.2 .6 1.4 .1-.1a1.63 1.63 0 0 1 .5-1.3l.2 .1a3.5 3.5 0 0 1-.8 2.1l-.2-.2-.5-1.2-.4 1.2-.4 .2zM172 106.4a.99 .99 0 0 1 1.3 .2l-.2 .2-.8-.1-.2 .2 .3 .2a.73 .73 0 0 1 1 .8 .73 .73 0 0 1-1.1 .6l-.5-.2-.1-.2 .1-.2 .9 .2 .3-.3-.4-.2a.84 .84 0 0 1-.9-.7zM171.7 115.1a2.43 2.43 0 0 1 3.8 .3 2.43 2.43 0 0 1-1.2 3.6 2.43 2.43 0 0 1-3.2-2v-.3h.3a1.99 1.99 0 0 0 2.7 2 1.99 1.99 0 0 0 .7-3.3 1.99 1.99 0 0 0-3.3 .8l-.1 .5h-.3l.1-.8zM172.8 116.1h1.3l-.3 2.3-.7 .1zM160.2 113.8l2.6-.2h16.8l4.9 .1 .8 .1 .1 8.8-24.9-.1h-.4v-.4h12.3l.6-.1a.49 .49 0 0 0 .1-.8l.1-.3-.4-.3h.5l.6 1.5 .3-.4h3.8l.5 .4h.8a.61 .61 0 0 1 .6-.4 .61 .61 0 0 1 .5 .4l.1-.1-.2-.8-.4-.6-.7 1.5h-.5a.45 .45 0 0 0 .5-.5 .45 .45 0 0 0-.6-.4l-.3-.2 .7 .1a.46 .46 0 0 0-.6-.5 .46 .46 0 0 0-.3 .7l.6 .3v.2l-.6-.2-.1 .1h-3.8l.4-1.1-.3 .1-.3 .5-.5-.6h-1.1l-.3 .2-.1 1.3h-11.9l-.1-6.5h.2v4.3l1 .1a3.8 3.8 0 0 0 6.6 0h17.5l-.1-4.5a2.21 2.21 0 0 0-.1-1.6l-24.1-.1a.51 .51 0 0 0-.6 .1 .51 .51 0 0 0-.2 .5v1.2h-.2zM173.9 106.6a.94 .94 0 0 1 1.1-.2 .94 .94 0 0 1 .5 1.1 .9 .9 0 0 1-.9 1 .9 .9 0 0 1-.9-1.1h.5v.5l.4 .2a.71 .71 0 0 0 .5-.7 .71 .71 0 0 0-.6-.7l-.3 .2v.5h-.5zM175.9 106.3h.5v1.2a.46 .46 0 0 0 .4 .6 .46 .46 0 0 0 .4-.7v-1l.4-.1v2.2l-.4-.1a.83 .83 0 0 1-1 0 .83 .83 0 0 1-.3-1zM175.6 109.9a.99 .99 0 0 1 1.2 0 .99 .99 0 0 1 .3 1.2v.9l-.4-.1a.85 .85 0 0 1-1.3-.6h.4a.45 .45 0 0 0 .5 .3 .45 .45 0 0 0 .4-.5l-1.3 .2a1.6 1.6 0 0 1 1.3-.8 .58 .58 0 0 0-.9-.2l-.3-.3zM177.6 109.8l.5 .2 .8-.2 .1 .2-.2 .2a.52 .52 0 0 0-.6 .1 .52 .52 0 0 0-.1 .5l-.1 1.1-.4 .1zM178.1 106.3h1.4l-.1 .4a.7 .7 0 0 0-.8 .2 .7 .7 0 0 0 0 .8l-.1 .7-.4 .1zM178.7 115.8a1.24 1.24 0 0 1 1.7 .3 1.24 1.24 0 0 1-.2 1.7 1.24 1.24 0 0 1-1.7-.1l-.1-.4h.5a.57 .57 0 0 0 .5 .4 .57 .57 0 0 0 .5-.3l.1-.4a.87 .87 0 0 0-.4-1 .49 .49 0 0 0-.6 .6l-.4 .3-.3-.3zM177.8 115a2.42 2.42 0 0 1 3.8 .6 2.42 2.42 0 0 1-1.4 3.5 2.42 2.42 0 0 1-3.1-2.1h.3a2 2 0 0 0 3 1.6 2 2 0 0 0 .2-3.4 2 2 0 0 0-3.1 1.3l-.1 .5-.3-.1a2.28 2.28 0 0 1 .7-1.9z"/>
<path d="M179.5 109.9a.94 .94 0 0 1 1.1 .1 .94 .94 0 0 1 .3 1l-1.3 .1a.56 .56 0 0 0 .3 .5 .56 .56 0 0 0 .6-.2l.3 .2a.99 .99 0 0 1-1.3 .2 .99 .99 0 0 1-.4-1.2l.9 .1 .4-.2a.43 .43 0 0 0-.6-.3l-.3 .4h-.4zM179.9 106.5a.88 .88 0 0 1 1.4 .2l-.2 .2a.68 .68 0 0 0-.9 .1 .68 .68 0 0 0 0 .9 .68 .68 0 0 0 .9 0l.2 .2a1.03 1.03 0 0 1-1.4 .2 1.03 1.03 0 0 1-.3-1.3zM181.8 106.6a.94 .94 0 0 1 1.1-.2 .94 .94 0 0 1 .4 1.1l-1.3 .1a.54 .54 0 0 0 .3 .5 .54 .54 0 0 0 .6-.1l.3 .2a.99 .99 0 0 1-1.3 .1 .99 .99 0 0 1-.4-1.2h1.3a.45 .45 0 0 0-.4-.4 .45 .45 0 0 0-.5 .4h-.4zM172.4 121.4l.4 .1 .1 .2h-.4zM172.4 120.9l.4 .1-.4 .1zM179.9 121.1v.4l-.2-.1z"/>
<circle cx="176.9" cy="82.6" r=".09"/>
<circle cx="173.5" cy="115.6" r=".31"/>
</g>
</svg>
